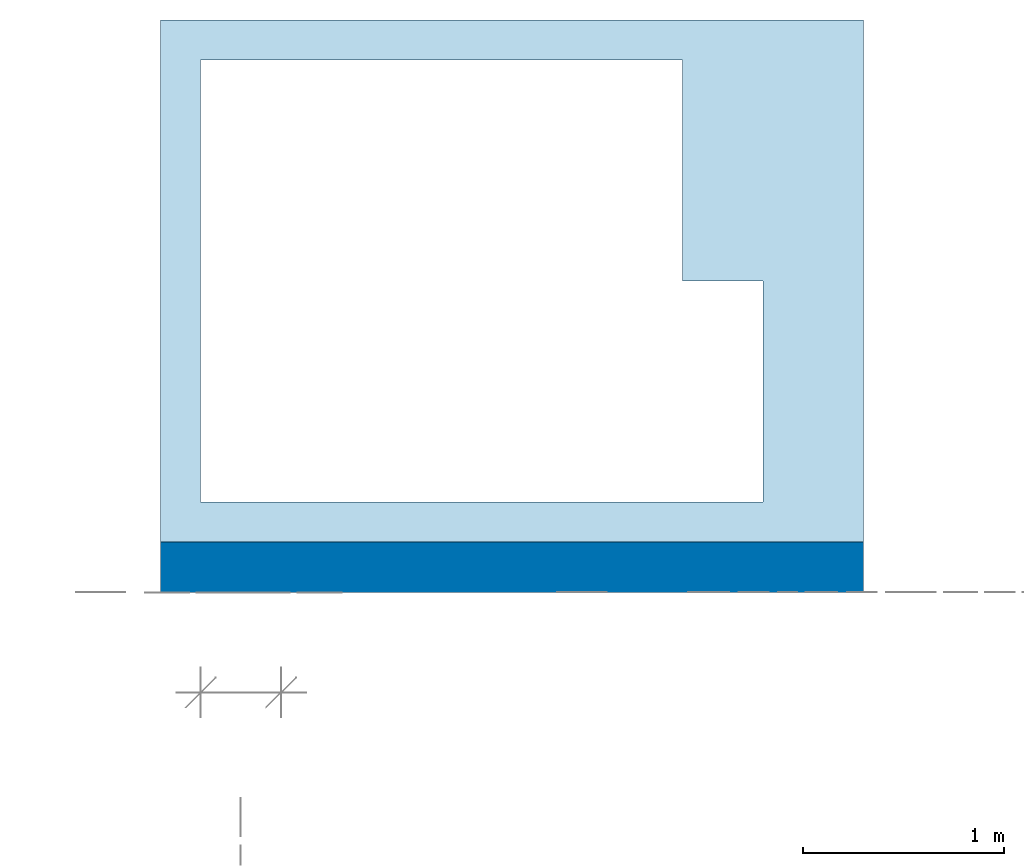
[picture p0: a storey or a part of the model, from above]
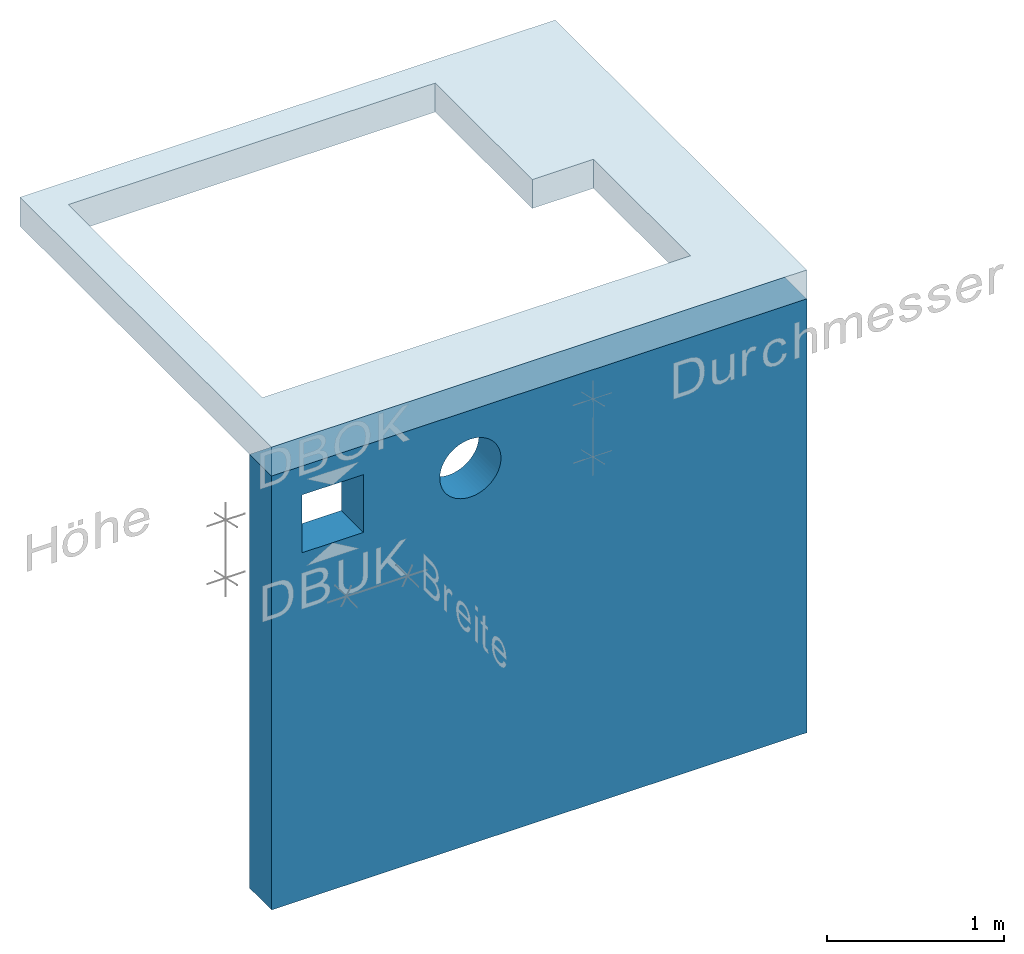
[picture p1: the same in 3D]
Properties of the parts of a building model (IFC4)

# File
Description: no view
File name: ÖBV_OEBV_Richtlinie_Durchbrüche.ifc
Time: 2024-03-13T09:54:18
Author: Oesterreichische Bautechnik Vereinigung
Organization: OEBV
Written by: ODA SDAI 24.5
Authorization: OEBV

# IfcSite, Liegenschaft
RefLatitude: 48, 8, 10, 320000; RefLongitude: 11, 41, 19, 320000

# IfcBuildingStorey, Geschoss 01
In: Gebäude
Elevation: 0 m

# IfcBuildingElementProxy (8)
In: Geschoss 01
Name | Allright_Bauteil_ID
macro | 0027Mak0000001021
macro | 0027Mak0000001043
macro | 0027Mak0000001054
macro | 0027Mak0000001067
macro | 0027Mak0000001078
 | 0027Mak0000001124
DBUK | 0027Mak0000001135
DBOK | 0027Mak0000001146

# IfcElementAssembly (8)
In: Geschoss 01
Name | Allright_Bauteil_ID
SpatialDim_Group | 0027Elg0000001022
SpatialDim_Group | 0027Elg0000001044
SpatialDim_Group | 0027Elg0000001055
SpatialDim_Group | 0027Elg0000001068
SpatialDim_Group | 0027Elg0000001079
SpatialDim_Group | 0027Elg0000001107
SpatialDim_Group | 0027Elg0000001136
SpatialDim_Group | 0027Elg0000001147

# IfcOpeningElement, DDB_01
In: Geschoss 01
Description: Deckendurchbruch; PredefinedType: OPENING
AllplanAttributes - Object Layer Attributes #1, Allright_Bauteil_ID: 0027Ddu0000000755

# IfcOpeningElement: Opening (2)
In: Geschoss 01
Name | Object Layer Attributes #1, Allright_Bauteil_ID
Wandnische | 0027Wdu0000000749
Wandnische | 0027Wdu0000000077

# IfcSlab, WA_01
In: Geschoss 01
Description: Innenwand; PredefinedType: FLOOR; Material: C25/30
AllplanAttributes - Allright_Bauteil_ID: 0027De 0000000044

# IfcWall, WA_01
In: Geschoss 01
Material: C25/30 0.25 m
AllplanAttributes - Allright_Bauteil_ID: 0027HWa0000000002; Object Layer Attributes #1, Allright_Bauteil_ID: 0027Wa 0000000048
